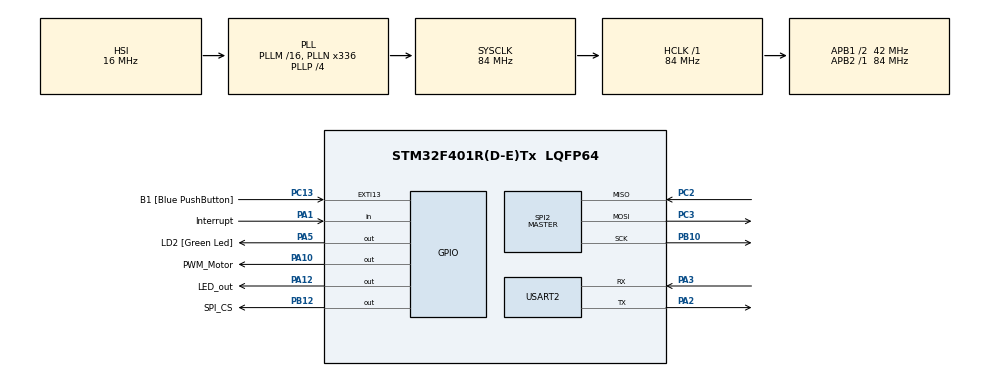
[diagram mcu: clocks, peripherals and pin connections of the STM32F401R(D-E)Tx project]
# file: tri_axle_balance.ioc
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FREERTOS.Queues01=qRawImu,8,RawImu_t,0,Dynamic,NULL,NULL;qAngles,4,AngleMsg_t,0,Dynamic,NULL,NULL
FREERTOS.Tasks01=defaultTask,24,128,StartDefaultTask,Default,NULL,Dynamic,NULL,NULL;Read_Angle_Volt,40,128,Read_Angle,Default,NULL,Dynamic,NULL,NULL;Angle_Convert,24,128,Angle_Conversion,Default,NULL,Dynamic,NULL,NULL;LED_Out,8,128,BlinkLED,Default,NULL,Dynamic,NULL,NULL;Print_Angle,16,128,Angle_Show,Default,NULL,Dynamic,NULL,NULL;Correct_angle,25,128,Angle_Correct,Default,NULL,Dynamic,NULL,NULL
Mcu.Family=STM32F4
Mcu.Name=STM32F401R(D-E)Tx
Mcu.Package=LQFP64
NVIC.EXTI15_10_IRQn=true\:15\:0\:true\:false\:true\:true\:true\:true\:true
NVIC.PriorityGroup=NVIC_PRIORITYGROUP_4
NVIC.SPI2_IRQn=true\:5\:0\:false\:false\:true\:true\:true\:true\:true
NVIC.TIM5_IRQn=true\:15\:0\:false\:false\:true\:false\:false\:true\:true
NVIC.TimeBase=TIM5_IRQn
NVIC.TimeBaseIP=TIM5
PA1.GPIO_Label=Interrupt
PA1.Signal=GPIO_Input
PA10.GPIO_Label=PWM_Motor
PA10.Signal=GPIO_Output
PA12.GPIO_Label=LED_out
PA12.Signal=GPIO_Output
PA13.GPIO_Label=TMS
PA13.Mode=Trace_Asynchronous_SW
PA13.Signal=SYS_JTMS-SWDIO
PA14.GPIO_Label=TCK
PA14.Mode=Trace_Asynchronous_SW
PA14.Signal=SYS_JTCK-SWCLK
PA2.Mode=Asynchronous
PA2.Signal=USART2_TX
PA3.Mode=Asynchronous
PA3.Signal=USART2_RX
PA5.GPIO_Label=LD2 [Green Led]
PA5.GPIO_Mode=GPIO_MODE_OUTPUT_PP
PA5.GPIO_PuPd=GPIO_NOPULL
PA5.GPIO_Speed=GPIO_SPEED_FREQ_LOW
PA5.Signal=GPIO_Output
PB10.Mode=Full_Duplex_Master
PB10.Signal=SPI2_SCK
PB12.GPIO_Label=SPI_CS
PB12.Signal=GPIO_Output
PB3.GPIO_Label=SWO
PB3.Mode=Trace_Asynchronous_SW
PB3.Signal=SYS_JTDO-SWO
PC13-ANTI_TAMP.GPIO_Label=B1 [Blue PushButton]
PC13-ANTI_TAMP.GPIO_ModeDefaultEXTI=GPIO_MODE_IT_FALLING
PC13-ANTI_TAMP.GPIO_PuPd=GPIO_NOPULL
PC13-ANTI_TAMP.Signal=GPXTI13
PC14-OSC32_IN.Mode=LSE-External-Oscillator
PC14-OSC32_IN.Signal=RCC_OSC32_IN
PC15-OSC32_OUT.Mode=LSE-External-Oscillator
PC15-OSC32_OUT.Signal=RCC_OSC32_OUT
PC2.Mode=Full_Duplex_Master
PC2.Signal=SPI2_MISO
PC3.Mode=Full_Duplex_Master
PC3.Signal=SPI2_MOSI
PH0\ -\ OSC_IN.Mode=HSE-External-Clock-Source
PH0\ -\ OSC_IN.Signal=RCC_OSC_IN
PH1\ -\ OSC_OUT.Mode=HSE-External-Clock-Source
PH1\ -\ OSC_OUT.Signal=RCC_OSC_OUT
ProjectManager.HeapSize=0x200
ProjectManager.StackSize=0x400
ProjectManager.TargetToolchain=STM32CubeIDE
RCC.48MHZClocksFreq_Value=48000000
RCC.AHBFreq_Value=84000000
RCC.APB1CLKDivider=RCC_HCLK_DIV2
RCC.APB1Freq_Value=42000000
RCC.APB1TimFreq_Value=84000000
RCC.APB2Freq_Value=84000000
RCC.APB2TimFreq_Value=84000000
RCC.CortexFreq_Value=84000000
RCC.HCLKFreq_Value=84000000
RCC.HSE_VALUE=8000000
RCC.HSI_VALUE=16000000
RCC.PLLN=336
RCC.PLLP=RCC_PLLP_DIV4
RCC.PLLQ=7
RCC.SYSCLKFreq_VALUE=84000000
RCC.SYSCLKSource=RCC_SYSCLKSOURCE_PLLCLK
RCC.VCOOutputFreq_Value=336000000
SPI2.CLKPhase=SPI_PHASE_2EDGE
SPI2.CLKPolarity=SPI_POLARITY_HIGH
SPI2.Direction=SPI_DIRECTION_2LINES
SPI2.Mode=SPI_MODE_MASTER
SPI2.VirtualType=VM_MASTER
USART2.VirtualMode=VM_ASYNC
VP_FREERTOS_VS_CMSIS_V2.Mode=CMSIS_V2
VP_SYS_VS_tim5.Mode=TIM5
board=NUCLEO-F401RE

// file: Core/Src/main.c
#include "main.h"
#include "cmsis_os.h"
#include <math.h>

#define		ADXL_DEVID		0x00
#define		ADXL_POWER_CTL	0x2D
#define		ADXL_DATA_FORMAT 0x31

#define		ADXL_READ		0x80
#define		ADXL_MULTI		0x40
#define 	ADXL_DATAX0		0x32
#define		FLAG_SPI_DONE	(1U << 0)
#define		FLAG_X_DONE		(1U << 1)
#define		FLAG_Y_DONE		(1U << 2)
#define		FLAG_Z_DONE		(1U << 3)

SPI_HandleTypeDef hspi2;

UART_HandleTypeDef huart2;

float referenceAngles[3];
float currentAngles[3];

typedef struct{
	float ax;
	float ay;
	float az;
	float angleX;
	float angleY;
	float angleZ;
}AngleMsg_t;

typedef struct{
	int16_t xRaw;			//Signed twos complement values from accelerometer
	int16_t yRaw;
	int16_t zRaw;
} RawImu_t;

uint8_t TX_Buffer[7];
uint8_t RX_Buffer[7]; //Initialize receive buffer for spi comms
uint8_t UART_TX_Buf[7];	//Uart buffer

/* Definitions for defaultTask */
osThreadId_t defaultTaskHandle;
const osThreadAttr_t defaultTask_attributes = {
  .name = "defaultTask",
  .stack_size = 128 * 4,
  .priority = (osPriority_t) osPriorityNormal,
};
/* Definitions for Read_Angle_Volt */
osThreadId_t Read_Angle_VoltHandle;
const osThreadAttr_t Read_Angle_Volt_attributes = {
  .name = "Read_Angle_Volt",
  .stack_size = 128 * 4,
  .priority = (osPriority_t) osPriorityHigh,
};

/* Definitions for Angle_Convert */
osThreadId_t Angle_ConvertHandle;
const osThreadAttr_t Angle_Convert_attributes = {
  .name = "Angle_Convert",
  .stack_size = 128 * 4,
  .priority = (osPriority_t) osPriorityNormal,
};
/* Definitions for LED_Out */
osThreadId_t LED_OutHandle;
const osThreadAttr_t LED_Out_attributes = {
  .name = "LED_Out",
  .stack_size = 128 * 4,
  .priority = (osPriority_t) osPriorityLow,
};
/* Definitions for Print_Angle */
osThreadId_t Print_AngleHandle;
const osThreadAttr_t Print_Angle_attributes = {
  .name = "Print_Angle",
  .stack_size = 128 * 4,
  .priority = (osPriority_t) osPriorityBelowNormal,
};
/* Definitions for Correct_angle */
osThreadId_t Correct_angleHandle;
const osThreadAttr_t Correct_angle_attributes = {
  .name = "Correct_angle",
  .stack_size = 128 * 4,
  .priority = (osPriority_t) osPriorityNormal1,
};
/* Definitions for qRawImu */
osMessageQueueId_t qRawImuHandle;
const osMessageQueueAttr_t qRawImu_attributes = {
  .name = "qRawImu"
};
/* Definitions for qAngles */
osMessageQueueId_t qAnglesHandle;
const osMessageQueueAttr_t qAngles_attributes = {
  .name = "qAngles"
};

void SystemClock_Config(void);
static void MX_GPIO_Init(void);
static void MX_SPI2_Init(void);
static void MX_USART2_UART_Init(void);
void initMotor(float baseX, float baseY, float baseZ);
void StartDefaultTask(void *argument);
void Read_Angle(void *argument);
void Angle_Conversion(void *argument);
void initADXL(void);
void BlinkLED(void *argument);
void Angle_Show(void *argument);
void Angle_Correct(void *argument);
void PWM_Step_1(void);
void PWM_Step_2(void);
void PWM_Step_3(void);
void PWM_Step_4(void);
void CW_Rotation(void);
void CCW_Rotation(void);
void Correct_X(AngleMsg_t *ang);
void Correct_Y(AngleMsg_t *ang);
void Correct_Z(AngleMsg_t *ang);

int main(void)
{

  /* MCU Configuration--------------------------------------------------------*/

  /* Reset of all peripherals, Initializes the Flash interface and the Systick. */
  HAL_Init();

  SystemClock_Config();

  /* Initialize all configured peripherals and motor*/
  MX_GPIO_Init();
  MX_SPI2_Init();
  MX_USART2_UART_Init();
  /*INSERT MOTOR BASELINE ANGLES BEFORE RUNNING*/
  initMotor(0.0f, 0.0f, 0.0f);
  initADXL();

  /* Init scheduler */
  osKernelInitialize();

  /* Create the queue(s) */
  /* creation of qRawImu */
  qRawImuHandle = osMessageQueueNew (8, sizeof(RawImu_t), &qRawImu_attributes);

  /* creation of qAngles */
  qAnglesHandle = osMessageQueueNew (4, sizeof(AngleMsg_t), &qAngles_attributes);

  /* Create the thread(s) */
  /* creation of defaultTask */
  defaultTaskHandle = osThreadNew(StartDefaultTask, NULL, &defaultTask_attributes);

  /* creation of Read_Angle_Volt */
  Read_Angle_VoltHandle = osThreadNew(Read_Angle, NULL, &Read_Angle_Volt_attributes);

  /* creation of Angle_Convert */
  Angle_ConvertHandle = osThreadNew(Angle_Conversion, NULL, &Angle_Convert_attributes);

  /* creation of LED_Out */
  LED_OutHandle = osThreadNew(BlinkLED, NULL, &LED_Out_attributes);

  /* creation of Print_Angle */
  Print_AngleHandle = osThreadNew(Angle_Show, NULL, &Print_Angle_attributes);

  /* creation of Correct_angle, rotates stepper motor to correct position */
  Correct_angleHandle = osThreadNew(Angle_Correct, NULL, &Correct_angle_attributes);

  /* Start scheduler */
  osKernelStart();

  /* We should never get here as control is now taken by the scheduler */

  /* Infinite loop */
  while (1)
  {
  }
}

void SystemClock_Config(void)
{
  RCC_OscInitTypeDef RCC_OscInitStruct = {0};
  RCC_ClkInitTypeDef RCC_ClkInitStruct = {0};

  /** Configure the main internal regulator output voltage
  */
  __HAL_RCC_PWR_CLK_ENABLE();
  __HAL_PWR_VOLTAGESCALING_CONFIG(PWR_REGULATOR_VOLTAGE_SCALE2);

  /** Initializes the RCC Oscillators according to the specified parameters
  * in the RCC_OscInitTypeDef structure.
  */
  RCC_OscInitStruct.OscillatorType = RCC_OSCILLATORTYPE_HSI;
  RCC_OscInitStruct.HSIState = RCC_HSI_ON;
  RCC_OscInitStruct.HSICalibrationValue = RCC_HSICALIBRATION_DEFAULT;
  RCC_OscInitStruct.PLL.PLLState = RCC_PLL_ON;
  RCC_OscInitStruct.PLL.PLLSource = RCC_PLLSOURCE_HSI;
  RCC_OscInitStruct.PLL.PLLM = 16;
  RCC_OscInitStruct.PLL.PLLN = 336;
  RCC_OscInitStruct.PLL.PLLP = RCC_PLLP_DIV4;
  RCC_OscInitStruct.PLL.PLLQ = 7;
  if (HAL_RCC_OscConfig(&RCC_OscInitStruct) != HAL_OK)
  {
    Error_Handler();
  }

  /** Initializes the CPU, AHB and APB buses clocks
  */
  RCC_ClkInitStruct.ClockType = RCC_CLOCKTYPE_HCLK|RCC_CLOCKTYPE_SYSCLK
                              |RCC_CLOCKTYPE_PCLK1|RCC_CLOCKTYPE_PCLK2;
  RCC_ClkInitStruct.SYSCLKSource = RCC_SYSCLKSOURCE_PLLCLK;
  RCC_ClkInitStruct.AHBCLKDivider = RCC_SYSCLK_DIV1;
  RCC_ClkInitStruct.APB1CLKDivider = RCC_HCLK_DIV2;
  RCC_ClkInitStruct.APB2CLKDivider = RCC_HCLK_DIV1;

  if (HAL_RCC_ClockConfig(&RCC_ClkInitStruct, FLASH_LATENCY_2) != HAL_OK)
  {
    Error_Handler();
  }
}

static void MX_SPI2_Init(void)
{

  /* SPI2 parameter configuration*/
  hspi2.Instance = SPI2;
  hspi2.Init.Mode = SPI_MODE_MASTER;
  hspi2.Init.Direction = SPI_DIRECTION_2LINES;
  hspi2.Init.DataSize = SPI_DATASIZE_8BIT;
  hspi2.Init.CLKPolarity = SPI_POLARITY_HIGH;
  hspi2.Init.CLKPhase = SPI_PHASE_2EDGE;
  hspi2.Init.NSS = SPI_NSS_SOFT;
  hspi2.Init.BaudRatePrescaler = SPI_BAUDRATEPRESCALER_2;
  hspi2.Init.FirstBit = SPI_FIRSTBIT_MSB;
  hspi2.Init.TIMode = SPI_TIMODE_DISABLE;
  hspi2.Init.CRCCalculation = SPI_CRCCALCULATION_DISABLE;
  hspi2.Init.CRCPolynomial = 10;
  if (HAL_SPI_Init(&hspi2) != HAL_OK)
  {
    Error_Handler();
  }

}

static void MX_USART2_UART_Init(void)
{

  huart2.Instance = USART2;
  huart2.Init.BaudRate = 115200;
  huart2.Init.WordLength = UART_WORDLENGTH_8B;
  huart2.Init.StopBits = UART_STOPBITS_1;
  huart2.Init.Parity = UART_PARITY_NONE;
  huart2.Init.Mode = UART_MODE_TX_RX;
  huart2.Init.HwFlowCtl = UART_HWCONTROL_NONE;
  huart2.Init.OverSampling = UART_OVERSAMPLING_16;
  if (HAL_UART_Init(&huart2) != HAL_OK)
  {
    Error_Handler();
  }

}

static void MX_GPIO_Init(void)
{
  GPIO_InitTypeDef GPIO_InitStruct = {0};

  /* GPIO Ports Clock Enable */
  __HAL_RCC_GPIOC_CLK_ENABLE();
  __HAL_RCC_GPIOH_CLK_ENABLE();
  __HAL_RCC_GPIOA_CLK_ENABLE();
  __HAL_RCC_GPIOB_CLK_ENABLE();

  /*Configure GPIO pin Output Level */
  HAL_GPIO_WritePin(GPIOA, LD2_Pin|Step_Pin_1_Pin|Step_PIN_2_Pin|Step_PIN_3_Pin
                          |Step_PIN_5_Pin|LED_out_Pin, GPIO_PIN_RESET);

  /*Configure GPIO pin Output Level */
  HAL_GPIO_WritePin(GPIOB, SPI_CS_Pin|ESP_SPI_CS_Pin, GPIO_PIN_RESET);

  /*Configure GPIO pin : B1_Pin */
  GPIO_InitStruct.Pin = B1_Pin;
  GPIO_InitStruct.Mode = GPIO_MODE_IT_FALLING;
  GPIO_InitStruct.Pull = GPIO_NOPULL;
  HAL_GPIO_Init(B1_GPIO_Port, &GPIO_InitStruct);

  /*Configure GPIO pin : ADXL_INT1_Pin */
  GPIO_InitStruct.Pin = ADXL_INT1_Pin;
  GPIO_InitStruct.Mode = GPIO_MODE_INPUT;
  GPIO_InitStruct.Pull = GPIO_NOPULL;
  HAL_GPIO_Init(ADXL_INT1_GPIO_Port, &GPIO_InitStruct);

  /*Configure GPIO pins : LD2_Pin Step_Pin_1_Pin Step_PIN_2_Pin Step_PIN_3_Pin
                           Step_PIN_5_Pin LED_out_Pin */
  GPIO_InitStruct.Pin = LD2_Pin|Step_Pin_1_Pin|Step_PIN_2_Pin|Step_PIN_3_Pin
                          |Step_PIN_5_Pin|LED_out_Pin;
  GPIO_InitStruct.Mode = GPIO_MODE_OUTPUT_PP;
  GPIO_InitStruct.Pull = GPIO_NOPULL;
  GPIO_InitStruct.Speed = GPIO_SPEED_FREQ_LOW;
  HAL_GPIO_Init(GPIOA, &GPIO_InitStruct);

  /*Configure GPIO pins : SPI_CS_Pin ESP_SPI_CS_Pin */
  GPIO_InitStruct.Pin = SPI_CS_Pin|ESP_SPI_CS_Pin;
  GPIO_InitStruct.Mode = GPIO_MODE_OUTPUT_PP;
  GPIO_InitStruct.Pull = GPIO_NOPULL;
  GPIO_InitStruct.Speed = GPIO_SPEED_FREQ_LOW;
  HAL_GPIO_Init(GPIOB, &GPIO_InitStruct);
  /* EXTI interrupt init*/
  HAL_NVIC_SetPriority(EXTI15_10_IRQn, 15, 0);
  HAL_NVIC_EnableIRQ(EXTI15_10_IRQn);

}

/*Set initial accelerometer angle baseline values*/
void initMotor(float baseX, float baseY, float baseZ){
	referenceAngles[0] = baseX;
	referenceAngles[1] = baseY;
	referenceAngles[2] = baseZ;
}

void initADXL(void){
	osDelay(2); //Wait for accelerometer to boot

}

//PWM Step functions for motor rotation
void PWM_Step_1(void){
	HAL_GPIO_WritePin(GPIOA, Step_Pin_1_Pin|Step_PIN_5_Pin, GPIO_PIN_SET);
	osDelay(1);
	HAL_GPIO_WritePin(GPIOA, Step_Pin_1_Pin|Step_PIN_5_Pin, GPIO_PIN_RESET);
}
void PWM_Step_2(void){
	HAL_GPIO_WritePin(GPIOA, Step_Pin_1_Pin|Step_PIN_2_Pin, GPIO_PIN_SET);
	osDelay(1);
	HAL_GPIO_WritePin(GPIOA, Step_Pin_1_Pin|Step_PIN_2_Pin, GPIO_PIN_RESET);
}
void PWM_Step_3(void){
	HAL_GPIO_WritePin(GPIOA, Step_PIN_2_Pin|Step_PIN_3_Pin, GPIO_PIN_SET);
	osDelay(1);
	HAL_GPIO_WritePin(GPIOA, Step_PIN_2_Pin|Step_PIN_3_Pin, GPIO_PIN_RESET);
}
void PWM_Step_4(void){
	HAL_GPIO_WritePin(GPIOA, Step_PIN_3_Pin|Step_PIN_5_Pin, GPIO_PIN_SET);
	osDelay(1);
	HAL_GPIO_WritePin(GPIOA, Step_PIN_3_Pin|Step_PIN_5_Pin, GPIO_PIN_RESET);
}

void CW_Rotation(void){
	PWM_Step_1();
	PWM_Step_2();
	PWM_Step_3();
	PWM_Step_4();
}

void CCW_Rotation(void){
	PWM_Step_4();
	PWM_Step_3();
	PWM_Step_2();
	PWM_Step_1();
}

void Correct_X(AngleMsg_t *ang){
	float error = referenceAngles[0] - ang->angleX;		//Sets tilt error value
	if(fabsf(error) <= 2.5f){		//Doesn't correct if error is less than +/- 2.5 degrees
		return;
	}
	if(error > 0){
		CW_Rotation();			//Rotates clockwise if error is positive
	}
	else{
		CCW_Rotation();		//Rotates ccw is error is negative (rotation directions based off unit circle)
	}
	osThreadFlagsSet(Angle_ConvertHandle, FLAG_X_DONE);
}
void Correct_Y(AngleMsg_t *ang){
	float error = referenceAngles[1] - ang->angleX;		//Sets tilt error value
	if(fabsf(error) <= 2.5f){		//Doesn't correct if error is less than +/- 2.5 degree
		return;
	}
	if(error > 0){
		CW_Rotation();			//Rotates clockwise if error is positive
	}
	else{
		CCW_Rotation();		//Rotates ccw is error is negative (rotation directions based off unit circle)
	}
	osThreadFlagsSet(Angle_ConvertHandle, FLAG_Y_DONE);
}
void Correct_Z(AngleMsg_t *ang){
	float error = referenceAngles[2] - ang->angleZ;
	if(fabsf(error) <= 1.0f){
		return;
	}
	if(error > 0){
		CW_Rotation();
	}
	else{
		CCW_Rotation();
	}
	osThreadFlagsSet(Angle_ConvertHandle, FLAG_Z_DONE);
}

void StartDefaultTask(void *argument) //Initialize baseline angles
{
  for(;;)
  {
    osDelay(1);
  }
}

void Read_Angle(void *argument)
{
  /* USER CODE BEGIN Read_Angle */
  RawImu_t raw;
  for(;;)
  {
	TX_Buffer[0] = ADXL_READ | ADXL_MULTI | ADXL_DATAX0; //Sets Transmission buffer with SPI command byte
    for(int i = 1; i < 7; i++){
    	TX_Buffer[i] = 0x00;							//Replaces all data in transmission buffer with 0
    }
    HAL_GPIO_WritePin(SPI_CS_GPIO_Port, SPI_CS_Pin, GPIO_PIN_RESET); //CS Low, enables ADXL to start transmitting data

    HAL_SPI_TransmitReceive_IT(&hspi2, TX_Buffer, RX_Buffer, 7);		//SPI_2 pointer, tx buffer, rx buffer, amount of data being exchanged

	osThreadFlagsWait(FLAG_SPI_DONE, osFlagsWaitAny, osWaitForever); /*Wait until transmission done. Transmission stopped in callback
	HAL_SPI_TxRxCpltCallback */

	//Move X, Y, and Z counts into variables. 16-bits for each axis
	raw.xRaw = (int16_t)((RX_Buffer[2] << 8) | RX_Buffer[1]);
	raw.yRaw = (int16_t)((RX_Buffer[4] << 8) | RX_Buffer[3]);
	raw.zRaw = (int16_t)((RX_Buffer[6] << 8) | RX_Buffer[5]);

	//Push to queue
	osMessageQueuePut(qRawImuHandle, &raw, 0, 0);
  }
  /* USER CODE END Read_Angle */
}

void Angle_Conversion(void *argument)
{
  /* USER CODE BEGIN Angle_Conversion */

	RawImu_t raw;
	AngleMsg_t ang;

  /* Infinite loop */
  for(;;)
  {
	  /*Get Voltage LSBs from RawImu queue*/
	  osMessageQueueGet(qRawImuHandle, &raw, NULL, osWaitForever);

	  /*Accelerometer gives digital counts per g, each LSB is 0.004g*/
	  ang.ax = raw.xRaw * 0.004f;   // acceleration in g
	  ang.ay = raw.yRaw * 0.004f;
	  ang.az = raw.zRaw * 0.004f;

	  ang.angleX = atan2(ang.ax, sqrt(ang.ay*ang.ay + ang.az*ang.az)) * 180.0 / M_PI;     // X-axis
	  ang.angleY = atan2(ang.ay, sqrt(ang.ax*ang.ax + ang.az*ang.az)) * 180.0 / M_PI;     // Y-axis
	  ang.angleZ = atan2(sqrt(ang.ax*ang.ax + ang.ay*ang.ay), ang.az) * 180.0 / M_PI;     // Z-axis

	  /*Push angles onto Angles queue*/
	  osMessageQueuePut(qAnglesHandle, &ang, 0, 0);
  }
  /* USER CODE END Angle_Conversion */
}

void BlinkLED(void *argument)
{
  for(;;)
  {
    osDelay(1);
  }
}

void Angle_Show(void *argument)
{
  /* USER CODE BEGIN Angle_Show */

  /* Infinite loop */
  for(;;)
  {
	  HAL_UART_Transmit_IT(&huart2, UART_TX_Buf, 7);
	  osDelay(1);
  }
  /* USER CODE END Angle_Show */
}

void Angle_Correct(void *argument)
{
  /* USER CODE BEGIN Angle_Correct */
	AngleMsg_t ang;
  /* Infinite loop */
  for(;;)
  {
	  osMessageQueueGet(qAnglesHandle, &ang, NULL, osWaitForever);
	  /*Motor is 28-BYJ84 Stepper motor, rotates 5.625 degrees per step,
	   * requires 64 steps to perform a 360 degree rotation*/

	  /*X axis (1 motor per axis)*/
	  Correct_X(&ang);
	  /*Y axis*/
	  Correct_Y(&ang);
	  /*Z axis*/
	  Correct_Z(&ang);
  }
  /* USER CODE END Angle_Correct */
}

void HAL_TIM_PeriodElapsedCallback(TIM_HandleTypeDef *htim)
{
  if (htim->Instance == TIM5)
  {
    HAL_IncTick();
  }
}
void HAL_SPI_TxRxCpltCallback(SPI_HandleTypeDef *hspi){
	if(hspi->Instance == SPI2){
		HAL_GPIO_WritePin(SPI_CS_GPIO_Port, SPI_CS_Pin, GPIO_PIN_SET); //CS HIGH
		osThreadFlagsSet(Read_Angle_VoltHandle, FLAG_SPI_DONE); //Wake task
	}
}

void Error_Handler(void)
{
  __disable_irq();
  while (1)
  {
  }
}
